VERSION 5.7 ;
  NOWIREEXTENSIONATPIN ON ;
  DIVIDERCHAR "/" ;
  BUSBITCHARS "[]" ;
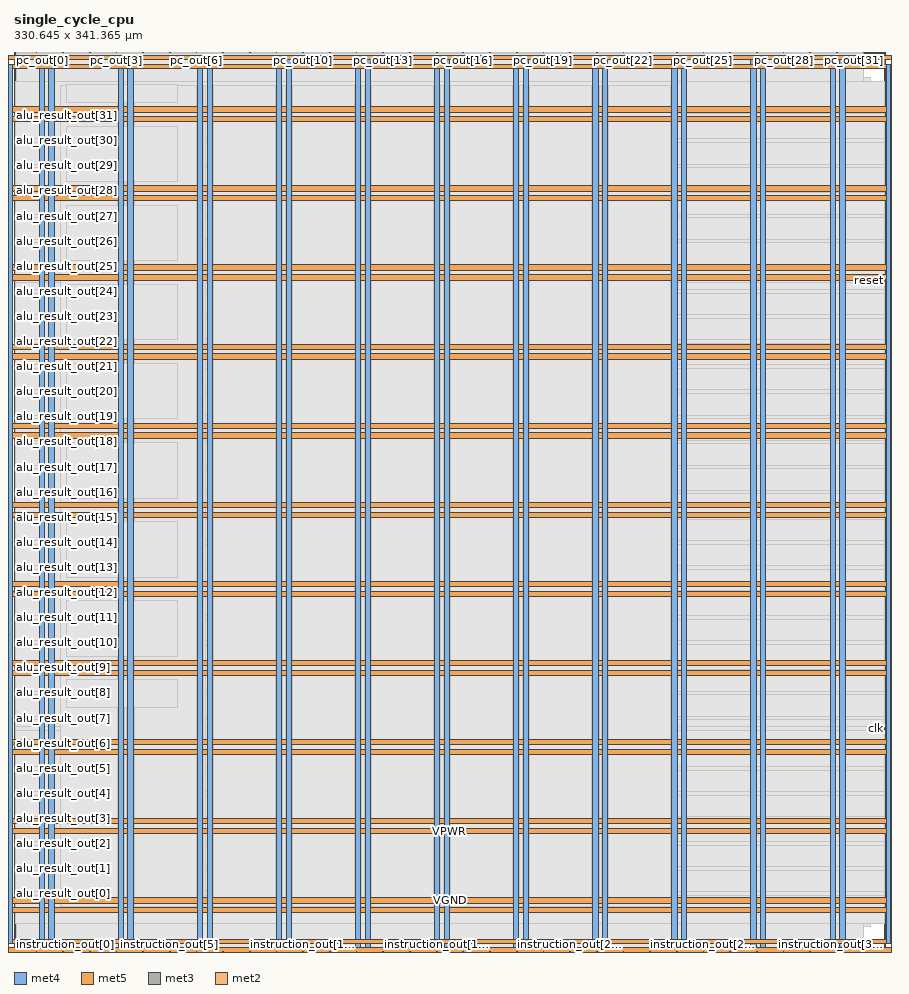
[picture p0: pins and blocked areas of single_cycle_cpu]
MACRO single_cycle_cpu
  CLASS BLOCK ;
  FOREIGN single_cycle_cpu ;
  ORIGIN 0.000 0.000 ;
  SIZE 330.645 BY 341.365 ;
  PIN VGND
    DIRECTION INOUT ;
    USE GROUND ;
    PORT
      LAYER met4 ;
        RECT -5.380 -0.020 -3.780 340.020 ;
    END
    PORT
      LAYER met4 ;
        RECT 334.060 -0.020 335.660 340.020 ;
    END
    PORT
      LAYER met5 ;
        RECT -5.380 -0.020 335.660 1.580 ;
    END
    PORT
      LAYER met5 ;
        RECT -5.380 338.420 335.660 340.020 ;
    END
    PORT
      LAYER met4 ;
        RECT 13.220 -0.020 15.220 340.020 ;
    END
    PORT
      LAYER met4 ;
        RECT 43.220 -0.020 45.220 340.020 ;
    END
    PORT
      LAYER met4 ;
        RECT 73.220 -0.020 75.220 340.020 ;
    END
    PORT
      LAYER met4 ;
        RECT 103.220 -0.020 105.220 340.020 ;
    END
    PORT
      LAYER met4 ;
        RECT 133.220 -0.020 135.220 340.020 ;
    END
    PORT
      LAYER met4 ;
        RECT 163.220 -0.020 165.220 340.020 ;
    END
    PORT
      LAYER met4 ;
        RECT 193.220 -0.020 195.220 340.020 ;
    END
    PORT
      LAYER met4 ;
        RECT 223.220 -0.020 225.220 340.020 ;
    END
    PORT
      LAYER met4 ;
        RECT 253.220 -0.020 255.220 340.020 ;
    END
    PORT
      LAYER met4 ;
        RECT 283.220 -0.020 285.220 340.020 ;
    END
    PORT
      LAYER met4 ;
        RECT 313.220 -0.020 315.220 340.020 ;
    END
    PORT
      LAYER met5 ;
        RECT -5.380 18.580 335.660 20.580 ;
    END
    PORT
      LAYER met5 ;
        RECT -5.380 48.580 335.660 50.580 ;
    END
    PORT
      LAYER met5 ;
        RECT -5.380 78.580 335.660 80.580 ;
    END
    PORT
      LAYER met5 ;
        RECT -5.380 108.580 335.660 110.580 ;
    END
    PORT
      LAYER met5 ;
        RECT -5.380 138.580 335.660 140.580 ;
    END
    PORT
      LAYER met5 ;
        RECT -5.380 168.580 335.660 170.580 ;
    END
    PORT
      LAYER met5 ;
        RECT -5.380 198.580 335.660 200.580 ;
    END
    PORT
      LAYER met5 ;
        RECT -5.380 228.580 335.660 230.580 ;
    END
    PORT
      LAYER met5 ;
        RECT -5.380 258.580 335.660 260.580 ;
    END
    PORT
      LAYER met5 ;
        RECT -5.380 288.580 335.660 290.580 ;
    END
    PORT
      LAYER met5 ;
        RECT -5.380 318.580 335.660 320.580 ;
    END
  END VGND
  PIN VPWR
    DIRECTION INOUT ;
    USE POWER ;
    PORT
      LAYER met4 ;
        RECT -2.080 3.280 -0.480 336.720 ;
    END
    PORT
      LAYER met4 ;
        RECT 330.760 3.280 332.360 336.720 ;
    END
    PORT
      LAYER met5 ;
        RECT -2.080 3.280 332.360 4.880 ;
    END
    PORT
      LAYER met5 ;
        RECT -2.080 335.120 332.360 336.720 ;
    END
    PORT
      LAYER met4 ;
        RECT 9.520 -0.020 11.520 340.020 ;
    END
    PORT
      LAYER met4 ;
        RECT 39.520 -0.020 41.520 340.020 ;
    END
    PORT
      LAYER met4 ;
        RECT 69.520 -0.020 71.520 340.020 ;
    END
    PORT
      LAYER met4 ;
        RECT 99.520 -0.020 101.520 340.020 ;
    END
    PORT
      LAYER met4 ;
        RECT 129.520 -0.020 131.520 340.020 ;
    END
    PORT
      LAYER met4 ;
        RECT 159.520 -0.020 161.520 340.020 ;
    END
    PORT
      LAYER met4 ;
        RECT 189.520 -0.020 191.520 340.020 ;
    END
    PORT
      LAYER met4 ;
        RECT 219.520 -0.020 221.520 340.020 ;
    END
    PORT
      LAYER met4 ;
        RECT 249.520 -0.020 251.520 340.020 ;
    END
    PORT
      LAYER met4 ;
        RECT 279.520 -0.020 281.520 340.020 ;
    END
    PORT
      LAYER met4 ;
        RECT 309.520 -0.020 311.520 340.020 ;
    END
    PORT
      LAYER met5 ;
        RECT -5.380 14.880 335.660 16.880 ;
    END
    PORT
      LAYER met5 ;
        RECT -5.380 44.880 335.660 46.880 ;
    END
    PORT
      LAYER met5 ;
        RECT -5.380 74.880 335.660 76.880 ;
    END
    PORT
      LAYER met5 ;
        RECT -5.380 104.880 335.660 106.880 ;
    END
    PORT
      LAYER met5 ;
        RECT -5.380 134.880 335.660 136.880 ;
    END
    PORT
      LAYER met5 ;
        RECT -5.380 164.880 335.660 166.880 ;
    END
    PORT
      LAYER met5 ;
        RECT -5.380 194.880 335.660 196.880 ;
    END
    PORT
      LAYER met5 ;
        RECT -5.380 224.880 335.660 226.880 ;
    END
    PORT
      LAYER met5 ;
        RECT -5.380 254.880 335.660 256.880 ;
    END
    PORT
      LAYER met5 ;
        RECT -5.380 284.880 335.660 286.880 ;
    END
    PORT
      LAYER met5 ;
        RECT -5.380 314.880 335.660 316.880 ;
    END
  END VPWR
  PIN alu_result_out[0]
    DIRECTION OUTPUT ;
    USE SIGNAL ;
    ANTENNADIFFAREA 0.702900 ;
    PORT
      LAYER met3 ;
        RECT 0.000 21.800 0.600 22.400 ;
    END
  END alu_result_out[0]
  PIN alu_result_out[10]
    DIRECTION OUTPUT ;
    USE SIGNAL ;
    ANTENNADIFFAREA 0.702900 ;
    PORT
      LAYER met3 ;
        RECT 0.000 117.000 0.600 117.600 ;
    END
  END alu_result_out[10]
  PIN alu_result_out[11]
    DIRECTION OUTPUT ;
    USE SIGNAL ;
    ANTENNADIFFAREA 0.702900 ;
    PORT
      LAYER met3 ;
        RECT 0.000 126.520 0.600 127.120 ;
    END
  END alu_result_out[11]
  PIN alu_result_out[12]
    DIRECTION OUTPUT ;
    USE SIGNAL ;
    ANTENNADIFFAREA 0.702900 ;
    PORT
      LAYER met3 ;
        RECT 0.000 136.040 0.600 136.640 ;
    END
  END alu_result_out[12]
  PIN alu_result_out[13]
    DIRECTION OUTPUT ;
    USE SIGNAL ;
    ANTENNADIFFAREA 0.702900 ;
    PORT
      LAYER met3 ;
        RECT 0.000 145.560 0.600 146.160 ;
    END
  END alu_result_out[13]
  PIN alu_result_out[14]
    DIRECTION OUTPUT ;
    USE SIGNAL ;
    ANTENNADIFFAREA 0.702900 ;
    PORT
      LAYER met3 ;
        RECT 0.000 155.080 0.600 155.680 ;
    END
  END alu_result_out[14]
  PIN alu_result_out[15]
    DIRECTION OUTPUT ;
    USE SIGNAL ;
    ANTENNADIFFAREA 0.702900 ;
    PORT
      LAYER met3 ;
        RECT 0.000 164.600 0.600 165.200 ;
    END
  END alu_result_out[15]
  PIN alu_result_out[16]
    DIRECTION OUTPUT ;
    USE SIGNAL ;
    ANTENNADIFFAREA 0.702900 ;
    PORT
      LAYER met3 ;
        RECT 0.000 174.120 0.600 174.720 ;
    END
  END alu_result_out[16]
  PIN alu_result_out[17]
    DIRECTION OUTPUT ;
    USE SIGNAL ;
    ANTENNADIFFAREA 0.702900 ;
    PORT
      LAYER met3 ;
        RECT 0.000 183.640 0.600 184.240 ;
    END
  END alu_result_out[17]
  PIN alu_result_out[18]
    DIRECTION OUTPUT ;
    USE SIGNAL ;
    ANTENNADIFFAREA 0.702900 ;
    PORT
      LAYER met3 ;
        RECT 0.000 193.160 0.600 193.760 ;
    END
  END alu_result_out[18]
  PIN alu_result_out[19]
    DIRECTION OUTPUT ;
    USE SIGNAL ;
    ANTENNADIFFAREA 0.702900 ;
    PORT
      LAYER met3 ;
        RECT 0.000 202.680 0.600 203.280 ;
    END
  END alu_result_out[19]
  PIN alu_result_out[1]
    DIRECTION OUTPUT ;
    USE SIGNAL ;
    ANTENNADIFFAREA 0.702900 ;
    PORT
      LAYER met3 ;
        RECT 0.000 31.320 0.600 31.920 ;
    END
  END alu_result_out[1]
  PIN alu_result_out[20]
    DIRECTION OUTPUT ;
    USE SIGNAL ;
    ANTENNADIFFAREA 0.702900 ;
    PORT
      LAYER met3 ;
        RECT 0.000 212.200 0.600 212.800 ;
    END
  END alu_result_out[20]
  PIN alu_result_out[21]
    DIRECTION OUTPUT ;
    USE SIGNAL ;
    ANTENNADIFFAREA 0.702900 ;
    PORT
      LAYER met3 ;
        RECT 0.000 221.720 0.600 222.320 ;
    END
  END alu_result_out[21]
  PIN alu_result_out[22]
    DIRECTION OUTPUT ;
    USE SIGNAL ;
    ANTENNADIFFAREA 0.702900 ;
    PORT
      LAYER met3 ;
        RECT 0.000 231.240 0.600 231.840 ;
    END
  END alu_result_out[22]
  PIN alu_result_out[23]
    DIRECTION OUTPUT ;
    USE SIGNAL ;
    ANTENNADIFFAREA 0.702900 ;
    PORT
      LAYER met3 ;
        RECT 0.000 240.760 0.600 241.360 ;
    END
  END alu_result_out[23]
  PIN alu_result_out[24]
    DIRECTION OUTPUT ;
    USE SIGNAL ;
    ANTENNADIFFAREA 0.702900 ;
    PORT
      LAYER met3 ;
        RECT 0.000 250.280 0.600 250.880 ;
    END
  END alu_result_out[24]
  PIN alu_result_out[25]
    DIRECTION OUTPUT ;
    USE SIGNAL ;
    ANTENNADIFFAREA 0.702900 ;
    PORT
      LAYER met3 ;
        RECT 0.000 259.800 0.600 260.400 ;
    END
  END alu_result_out[25]
  PIN alu_result_out[26]
    DIRECTION OUTPUT ;
    USE SIGNAL ;
    ANTENNADIFFAREA 0.702900 ;
    PORT
      LAYER met3 ;
        RECT 0.000 269.320 0.600 269.920 ;
    END
  END alu_result_out[26]
  PIN alu_result_out[27]
    DIRECTION OUTPUT ;
    USE SIGNAL ;
    ANTENNADIFFAREA 0.702900 ;
    PORT
      LAYER met3 ;
        RECT 0.000 278.840 0.600 279.440 ;
    END
  END alu_result_out[27]
  PIN alu_result_out[28]
    DIRECTION OUTPUT ;
    USE SIGNAL ;
    ANTENNADIFFAREA 0.702900 ;
    PORT
      LAYER met3 ;
        RECT 0.000 288.360 0.600 288.960 ;
    END
  END alu_result_out[28]
  PIN alu_result_out[29]
    DIRECTION OUTPUT ;
    USE SIGNAL ;
    ANTENNADIFFAREA 0.702900 ;
    PORT
      LAYER met3 ;
        RECT 0.000 297.880 0.600 298.480 ;
    END
  END alu_result_out[29]
  PIN alu_result_out[2]
    DIRECTION OUTPUT ;
    USE SIGNAL ;
    ANTENNADIFFAREA 0.702900 ;
    PORT
      LAYER met3 ;
        RECT 0.000 40.840 0.600 41.440 ;
    END
  END alu_result_out[2]
  PIN alu_result_out[30]
    DIRECTION OUTPUT ;
    USE SIGNAL ;
    ANTENNADIFFAREA 0.702900 ;
    PORT
      LAYER met3 ;
        RECT 0.000 307.400 0.600 308.000 ;
    END
  END alu_result_out[30]
  PIN alu_result_out[31]
    DIRECTION OUTPUT ;
    USE SIGNAL ;
    ANTENNADIFFAREA 0.702900 ;
    PORT
      LAYER met3 ;
        RECT 0.000 316.920 0.600 317.520 ;
    END
  END alu_result_out[31]
  PIN alu_result_out[3]
    DIRECTION OUTPUT ;
    USE SIGNAL ;
    ANTENNADIFFAREA 0.702900 ;
    PORT
      LAYER met3 ;
        RECT 0.000 50.360 0.600 50.960 ;
    END
  END alu_result_out[3]
  PIN alu_result_out[4]
    DIRECTION OUTPUT ;
    USE SIGNAL ;
    ANTENNADIFFAREA 0.702900 ;
    PORT
      LAYER met3 ;
        RECT 0.000 59.880 0.600 60.480 ;
    END
  END alu_result_out[4]
  PIN alu_result_out[5]
    DIRECTION OUTPUT ;
    USE SIGNAL ;
    ANTENNADIFFAREA 0.702900 ;
    PORT
      LAYER met3 ;
        RECT 0.000 69.400 0.600 70.000 ;
    END
  END alu_result_out[5]
  PIN alu_result_out[6]
    DIRECTION OUTPUT ;
    USE SIGNAL ;
    ANTENNADIFFAREA 0.702900 ;
    PORT
      LAYER met3 ;
        RECT 0.000 78.920 0.600 79.520 ;
    END
  END alu_result_out[6]
  PIN alu_result_out[7]
    DIRECTION OUTPUT ;
    USE SIGNAL ;
    ANTENNADIFFAREA 0.702900 ;
    PORT
      LAYER met3 ;
        RECT 0.000 88.440 0.600 89.040 ;
    END
  END alu_result_out[7]
  PIN alu_result_out[8]
    DIRECTION OUTPUT ;
    USE SIGNAL ;
    ANTENNADIFFAREA 0.702900 ;
    PORT
      LAYER met3 ;
        RECT 0.000 97.960 0.600 98.560 ;
    END
  END alu_result_out[8]
  PIN alu_result_out[9]
    DIRECTION OUTPUT ;
    USE SIGNAL ;
    ANTENNADIFFAREA 0.702900 ;
    PORT
      LAYER met3 ;
        RECT 0.000 107.480 0.600 108.080 ;
    END
  END alu_result_out[9]
  PIN clk
    DIRECTION INPUT ;
    USE SIGNAL ;
    ANTENNAGATEAREA 0.852000 ;
    PORT
      LAYER met3 ;
        RECT 330.045 84.360 330.645 84.960 ;
    END
  END clk
  PIN instruction_out[0]
    DIRECTION OUTPUT ;
    USE SIGNAL ;
    PORT
      LAYER met2 ;
        RECT 8.370 0.000 8.650 0.280 ;
    END
  END instruction_out[0]
  PIN instruction_out[10]
    DIRECTION OUTPUT ;
    USE SIGNAL ;
    ANTENNADIFFAREA 0.702900 ;
    PORT
      LAYER met2 ;
        RECT 109.570 0.000 109.850 0.280 ;
    END
  END instruction_out[10]
  PIN instruction_out[11]
    DIRECTION OUTPUT ;
    USE SIGNAL ;
    ANTENNADIFFAREA 0.702900 ;
    PORT
      LAYER met2 ;
        RECT 119.690 0.000 119.970 0.280 ;
    END
  END instruction_out[11]
  PIN instruction_out[12]
    DIRECTION OUTPUT ;
    USE SIGNAL ;
    ANTENNADIFFAREA 0.702900 ;
    PORT
      LAYER met2 ;
        RECT 129.810 0.000 130.090 0.280 ;
    END
  END instruction_out[12]
  PIN instruction_out[13]
    DIRECTION OUTPUT ;
    USE SIGNAL ;
    ANTENNADIFFAREA 0.702900 ;
    PORT
      LAYER met2 ;
        RECT 139.930 0.000 140.210 0.280 ;
    END
  END instruction_out[13]
  PIN instruction_out[14]
    DIRECTION OUTPUT ;
    USE SIGNAL ;
    ANTENNADIFFAREA 0.702900 ;
    PORT
      LAYER met2 ;
        RECT 150.050 0.000 150.330 0.280 ;
    END
  END instruction_out[14]
  PIN instruction_out[15]
    DIRECTION OUTPUT ;
    USE SIGNAL ;
    ANTENNADIFFAREA 0.702900 ;
    PORT
      LAYER met2 ;
        RECT 160.170 0.000 160.450 0.280 ;
    END
  END instruction_out[15]
  PIN instruction_out[16]
    DIRECTION OUTPUT ;
    USE SIGNAL ;
    ANTENNADIFFAREA 0.702900 ;
    PORT
      LAYER met2 ;
        RECT 170.290 0.000 170.570 0.280 ;
    END
  END instruction_out[16]
  PIN instruction_out[17]
    DIRECTION OUTPUT ;
    USE SIGNAL ;
    ANTENNADIFFAREA 0.702900 ;
    PORT
      LAYER met2 ;
        RECT 180.410 0.000 180.690 0.280 ;
    END
  END instruction_out[17]
  PIN instruction_out[18]
    DIRECTION OUTPUT ;
    USE SIGNAL ;
    ANTENNADIFFAREA 0.702900 ;
    PORT
      LAYER met2 ;
        RECT 190.530 0.000 190.810 0.280 ;
    END
  END instruction_out[18]
  PIN instruction_out[19]
    DIRECTION OUTPUT ;
    USE SIGNAL ;
    PORT
      LAYER met2 ;
        RECT 200.650 0.000 200.930 0.280 ;
    END
  END instruction_out[19]
  PIN instruction_out[1]
    DIRECTION OUTPUT ;
    USE SIGNAL ;
    PORT
      LAYER met2 ;
        RECT 18.490 0.000 18.770 0.280 ;
    END
  END instruction_out[1]
  PIN instruction_out[20]
    DIRECTION OUTPUT ;
    USE SIGNAL ;
    ANTENNADIFFAREA 0.702900 ;
    PORT
      LAYER met2 ;
        RECT 210.770 0.000 211.050 0.280 ;
    END
  END instruction_out[20]
  PIN instruction_out[21]
    DIRECTION OUTPUT ;
    USE SIGNAL ;
    ANTENNADIFFAREA 0.702900 ;
    PORT
      LAYER met2 ;
        RECT 220.890 0.000 221.170 0.280 ;
    END
  END instruction_out[21]
  PIN instruction_out[22]
    DIRECTION OUTPUT ;
    USE SIGNAL ;
    ANTENNADIFFAREA 0.702900 ;
    PORT
      LAYER met2 ;
        RECT 231.010 0.000 231.290 0.280 ;
    END
  END instruction_out[22]
  PIN instruction_out[23]
    DIRECTION OUTPUT ;
    USE SIGNAL ;
    ANTENNADIFFAREA 0.702900 ;
    PORT
      LAYER met2 ;
        RECT 241.130 0.000 241.410 0.280 ;
    END
  END instruction_out[23]
  PIN instruction_out[24]
    DIRECTION OUTPUT ;
    USE SIGNAL ;
    ANTENNADIFFAREA 0.702900 ;
    PORT
      LAYER met2 ;
        RECT 251.250 0.000 251.530 0.280 ;
    END
  END instruction_out[24]
  PIN instruction_out[25]
    DIRECTION OUTPUT ;
    USE SIGNAL ;
    ANTENNADIFFAREA 0.702900 ;
    PORT
      LAYER met2 ;
        RECT 261.370 0.000 261.650 0.280 ;
    END
  END instruction_out[25]
  PIN instruction_out[26]
    DIRECTION OUTPUT ;
    USE SIGNAL ;
    ANTENNADIFFAREA 0.702900 ;
    PORT
      LAYER met2 ;
        RECT 271.490 0.000 271.770 0.280 ;
    END
  END instruction_out[26]
  PIN instruction_out[27]
    DIRECTION OUTPUT ;
    USE SIGNAL ;
    ANTENNADIFFAREA 0.702900 ;
    PORT
      LAYER met2 ;
        RECT 281.610 0.000 281.890 0.280 ;
    END
  END instruction_out[27]
  PIN instruction_out[28]
    DIRECTION OUTPUT ;
    USE SIGNAL ;
    ANTENNADIFFAREA 0.702900 ;
    PORT
      LAYER met2 ;
        RECT 291.730 0.000 292.010 0.280 ;
    END
  END instruction_out[28]
  PIN instruction_out[29]
    DIRECTION OUTPUT ;
    USE SIGNAL ;
    PORT
      LAYER met2 ;
        RECT 301.850 0.000 302.130 0.280 ;
    END
  END instruction_out[29]
  PIN instruction_out[2]
    DIRECTION OUTPUT ;
    USE SIGNAL ;
    ANTENNADIFFAREA 0.702900 ;
    PORT
      LAYER met2 ;
        RECT 28.610 0.000 28.890 0.280 ;
    END
  END instruction_out[2]
  PIN instruction_out[30]
    DIRECTION OUTPUT ;
    USE SIGNAL ;
    ANTENNADIFFAREA 0.702900 ;
    PORT
      LAYER met2 ;
        RECT 311.970 0.000 312.250 0.280 ;
    END
  END instruction_out[30]
  PIN instruction_out[31]
    DIRECTION OUTPUT ;
    USE SIGNAL ;
    PORT
      LAYER met2 ;
        RECT 322.090 0.000 322.370 0.280 ;
    END
  END instruction_out[31]
  PIN instruction_out[3]
    DIRECTION OUTPUT ;
    USE SIGNAL ;
    ANTENNADIFFAREA 0.702900 ;
    PORT
      LAYER met2 ;
        RECT 38.730 0.000 39.010 0.280 ;
    END
  END instruction_out[3]
  PIN instruction_out[4]
    DIRECTION OUTPUT ;
    USE SIGNAL ;
    ANTENNADIFFAREA 0.702900 ;
    PORT
      LAYER met2 ;
        RECT 48.850 0.000 49.130 0.280 ;
    END
  END instruction_out[4]
  PIN instruction_out[5]
    DIRECTION OUTPUT ;
    USE SIGNAL ;
    ANTENNADIFFAREA 0.702900 ;
    PORT
      LAYER met2 ;
        RECT 58.970 0.000 59.250 0.280 ;
    END
  END instruction_out[5]
  PIN instruction_out[6]
    DIRECTION OUTPUT ;
    USE SIGNAL ;
    ANTENNADIFFAREA 0.702900 ;
    PORT
      LAYER met2 ;
        RECT 69.090 0.000 69.370 0.280 ;
    END
  END instruction_out[6]
  PIN instruction_out[7]
    DIRECTION OUTPUT ;
    USE SIGNAL ;
    ANTENNADIFFAREA 0.702900 ;
    PORT
      LAYER met2 ;
        RECT 79.210 0.000 79.490 0.280 ;
    END
  END instruction_out[7]
  PIN instruction_out[8]
    DIRECTION OUTPUT ;
    USE SIGNAL ;
    ANTENNADIFFAREA 0.702900 ;
    PORT
      LAYER met2 ;
        RECT 89.330 0.000 89.610 0.280 ;
    END
  END instruction_out[8]
  PIN instruction_out[9]
    DIRECTION OUTPUT ;
    USE SIGNAL ;
    ANTENNADIFFAREA 0.702900 ;
    PORT
      LAYER met2 ;
        RECT 99.450 0.000 99.730 0.280 ;
    END
  END instruction_out[9]
  PIN pc_out[0]
    DIRECTION OUTPUT ;
    USE SIGNAL ;
    ANTENNADIFFAREA 0.702900 ;
    PORT
      LAYER met2 ;
        RECT 8.370 341.085 8.650 341.365 ;
    END
  END pc_out[0]
  PIN pc_out[10]
    DIRECTION OUTPUT ;
    USE SIGNAL ;
    ANTENNADIFFAREA 0.702900 ;
    PORT
      LAYER met2 ;
        RECT 109.570 341.085 109.850 341.365 ;
    END
  END pc_out[10]
  PIN pc_out[11]
    DIRECTION OUTPUT ;
    USE SIGNAL ;
    ANTENNADIFFAREA 0.702900 ;
    PORT
      LAYER met2 ;
        RECT 119.690 341.085 119.970 341.365 ;
    END
  END pc_out[11]
  PIN pc_out[12]
    DIRECTION OUTPUT ;
    USE SIGNAL ;
    ANTENNADIFFAREA 0.702900 ;
    PORT
      LAYER met2 ;
        RECT 129.810 341.085 130.090 341.365 ;
    END
  END pc_out[12]
  PIN pc_out[13]
    DIRECTION OUTPUT ;
    USE SIGNAL ;
    ANTENNADIFFAREA 0.702900 ;
    PORT
      LAYER met2 ;
        RECT 139.930 341.085 140.210 341.365 ;
    END
  END pc_out[13]
  PIN pc_out[14]
    DIRECTION OUTPUT ;
    USE SIGNAL ;
    ANTENNADIFFAREA 0.702900 ;
    PORT
      LAYER met2 ;
        RECT 150.050 341.085 150.330 341.365 ;
    END
  END pc_out[14]
  PIN pc_out[15]
    DIRECTION OUTPUT ;
    USE SIGNAL ;
    ANTENNADIFFAREA 0.702900 ;
    PORT
      LAYER met2 ;
        RECT 160.170 341.085 160.450 341.365 ;
    END
  END pc_out[15]
  PIN pc_out[16]
    DIRECTION OUTPUT ;
    USE SIGNAL ;
    ANTENNADIFFAREA 0.702900 ;
    PORT
      LAYER met2 ;
        RECT 170.290 341.085 170.570 341.365 ;
    END
  END pc_out[16]
  PIN pc_out[17]
    DIRECTION OUTPUT ;
    USE SIGNAL ;
    ANTENNADIFFAREA 0.702900 ;
    PORT
      LAYER met2 ;
        RECT 180.410 341.085 180.690 341.365 ;
    END
  END pc_out[17]
  PIN pc_out[18]
    DIRECTION OUTPUT ;
    USE SIGNAL ;
    ANTENNADIFFAREA 0.702900 ;
    PORT
      LAYER met2 ;
        RECT 190.530 341.085 190.810 341.365 ;
    END
  END pc_out[18]
  PIN pc_out[19]
    DIRECTION OUTPUT ;
    USE SIGNAL ;
    ANTENNADIFFAREA 0.702900 ;
    PORT
      LAYER met2 ;
        RECT 200.650 341.085 200.930 341.365 ;
    END
  END pc_out[19]
  PIN pc_out[1]
    DIRECTION OUTPUT ;
    USE SIGNAL ;
    ANTENNADIFFAREA 0.702900 ;
    PORT
      LAYER met2 ;
        RECT 18.490 341.085 18.770 341.365 ;
    END
  END pc_out[1]
  PIN pc_out[20]
    DIRECTION OUTPUT ;
    USE SIGNAL ;
    ANTENNADIFFAREA 0.702900 ;
    PORT
      LAYER met2 ;
        RECT 210.770 341.085 211.050 341.365 ;
    END
  END pc_out[20]
  PIN pc_out[21]
    DIRECTION OUTPUT ;
    USE SIGNAL ;
    ANTENNADIFFAREA 0.702900 ;
    PORT
      LAYER met2 ;
        RECT 220.890 341.085 221.170 341.365 ;
    END
  END pc_out[21]
  PIN pc_out[22]
    DIRECTION OUTPUT ;
    USE SIGNAL ;
    ANTENNADIFFAREA 0.702900 ;
    PORT
      LAYER met2 ;
        RECT 231.010 341.085 231.290 341.365 ;
    END
  END pc_out[22]
  PIN pc_out[23]
    DIRECTION OUTPUT ;
    USE SIGNAL ;
    ANTENNADIFFAREA 0.702900 ;
    PORT
      LAYER met2 ;
        RECT 241.130 341.085 241.410 341.365 ;
    END
  END pc_out[23]
  PIN pc_out[24]
    DIRECTION OUTPUT ;
    USE SIGNAL ;
    ANTENNADIFFAREA 0.702900 ;
    PORT
      LAYER met2 ;
        RECT 251.250 341.085 251.530 341.365 ;
    END
  END pc_out[24]
  PIN pc_out[25]
    DIRECTION OUTPUT ;
    USE SIGNAL ;
    ANTENNADIFFAREA 0.702900 ;
    PORT
      LAYER met2 ;
        RECT 261.370 341.085 261.650 341.365 ;
    END
  END pc_out[25]
  PIN pc_out[26]
    DIRECTION OUTPUT ;
    USE SIGNAL ;
    ANTENNADIFFAREA 0.702900 ;
    PORT
      LAYER met2 ;
        RECT 271.490 341.085 271.770 341.365 ;
    END
  END pc_out[26]
  PIN pc_out[27]
    DIRECTION OUTPUT ;
    USE SIGNAL ;
    ANTENNADIFFAREA 0.702900 ;
    PORT
      LAYER met2 ;
        RECT 281.610 341.085 281.890 341.365 ;
    END
  END pc_out[27]
  PIN pc_out[28]
    DIRECTION OUTPUT ;
    USE SIGNAL ;
    ANTENNADIFFAREA 0.702900 ;
    PORT
      LAYER met2 ;
        RECT 291.730 341.085 292.010 341.365 ;
    END
  END pc_out[28]
  PIN pc_out[29]
    DIRECTION OUTPUT ;
    USE SIGNAL ;
    ANTENNADIFFAREA 0.702900 ;
    PORT
      LAYER met2 ;
        RECT 301.850 341.085 302.130 341.365 ;
    END
  END pc_out[29]
  PIN pc_out[2]
    DIRECTION OUTPUT ;
    USE SIGNAL ;
    ANTENNADIFFAREA 0.702900 ;
    PORT
      LAYER met2 ;
        RECT 28.610 341.085 28.890 341.365 ;
    END
  END pc_out[2]
  PIN pc_out[30]
    DIRECTION OUTPUT ;
    USE SIGNAL ;
    ANTENNADIFFAREA 0.702900 ;
    PORT
      LAYER met2 ;
        RECT 311.970 341.085 312.250 341.365 ;
    END
  END pc_out[30]
  PIN pc_out[31]
    DIRECTION OUTPUT ;
    USE SIGNAL ;
    ANTENNADIFFAREA 0.702900 ;
    PORT
      LAYER met2 ;
        RECT 322.090 341.085 322.370 341.365 ;
    END
  END pc_out[31]
  PIN pc_out[3]
    DIRECTION OUTPUT ;
    USE SIGNAL ;
    ANTENNADIFFAREA 0.702900 ;
    PORT
      LAYER met2 ;
        RECT 38.730 341.085 39.010 341.365 ;
    END
  END pc_out[3]
  PIN pc_out[4]
    DIRECTION OUTPUT ;
    USE SIGNAL ;
    ANTENNADIFFAREA 0.702900 ;
    PORT
      LAYER met2 ;
        RECT 48.850 341.085 49.130 341.365 ;
    END
  END pc_out[4]
  PIN pc_out[5]
    DIRECTION OUTPUT ;
    USE SIGNAL ;
    ANTENNADIFFAREA 0.702900 ;
    PORT
      LAYER met2 ;
        RECT 58.970 341.085 59.250 341.365 ;
    END
  END pc_out[5]
  PIN pc_out[6]
    DIRECTION OUTPUT ;
    USE SIGNAL ;
    ANTENNADIFFAREA 0.702900 ;
    PORT
      LAYER met2 ;
        RECT 69.090 341.085 69.370 341.365 ;
    END
  END pc_out[6]
  PIN pc_out[7]
    DIRECTION OUTPUT ;
    USE SIGNAL ;
    ANTENNADIFFAREA 0.702900 ;
    PORT
      LAYER met2 ;
        RECT 79.210 341.085 79.490 341.365 ;
    END
  END pc_out[7]
  PIN pc_out[8]
    DIRECTION OUTPUT ;
    USE SIGNAL ;
    ANTENNADIFFAREA 0.702900 ;
    PORT
      LAYER met2 ;
        RECT 89.330 341.085 89.610 341.365 ;
    END
  END pc_out[8]
  PIN pc_out[9]
    DIRECTION OUTPUT ;
    USE SIGNAL ;
    ANTENNADIFFAREA 0.702900 ;
    PORT
      LAYER met2 ;
        RECT 99.450 341.085 99.730 341.365 ;
    END
  END pc_out[9]
  PIN reset
    DIRECTION INPUT ;
    USE SIGNAL ;
    ANTENNAGATEAREA 0.393000 ;
    PORT
      LAYER met3 ;
        RECT 330.045 254.360 330.645 254.960 ;
    END
  END reset
  OBS
      LAYER nwell ;
        RECT 5.330 10.795 324.950 329.310 ;
      LAYER li1 ;
        RECT 5.520 10.795 324.760 329.205 ;
      LAYER met1 ;
        RECT 0.990 9.560 324.760 331.800 ;
      LAYER met2 ;
        RECT 1.010 340.805 8.090 341.295 ;
        RECT 8.930 340.805 18.210 341.295 ;
        RECT 19.050 340.805 28.330 341.295 ;
        RECT 29.170 340.805 38.450 341.295 ;
        RECT 39.290 340.805 48.570 341.295 ;
        RECT 49.410 340.805 58.690 341.295 ;
        RECT 59.530 340.805 68.810 341.295 ;
        RECT 69.650 340.805 78.930 341.295 ;
        RECT 79.770 340.805 89.050 341.295 ;
        RECT 89.890 340.805 99.170 341.295 ;
        RECT 100.010 340.805 109.290 341.295 ;
        RECT 110.130 340.805 119.410 341.295 ;
        RECT 120.250 340.805 129.530 341.295 ;
        RECT 130.370 340.805 139.650 341.295 ;
        RECT 140.490 340.805 149.770 341.295 ;
        RECT 150.610 340.805 159.890 341.295 ;
        RECT 160.730 340.805 170.010 341.295 ;
        RECT 170.850 340.805 180.130 341.295 ;
        RECT 180.970 340.805 190.250 341.295 ;
        RECT 191.090 340.805 200.370 341.295 ;
        RECT 201.210 340.805 210.490 341.295 ;
        RECT 211.330 340.805 220.610 341.295 ;
        RECT 221.450 340.805 230.730 341.295 ;
        RECT 231.570 340.805 240.850 341.295 ;
        RECT 241.690 340.805 250.970 341.295 ;
        RECT 251.810 340.805 261.090 341.295 ;
        RECT 261.930 340.805 271.210 341.295 ;
        RECT 272.050 340.805 281.330 341.295 ;
        RECT 282.170 340.805 291.450 341.295 ;
        RECT 292.290 340.805 301.570 341.295 ;
        RECT 302.410 340.805 311.690 341.295 ;
        RECT 312.530 340.805 321.810 341.295 ;
        RECT 1.010 0.560 322.360 340.805 ;
        RECT 1.010 0.070 8.090 0.560 ;
        RECT 8.930 0.070 18.210 0.560 ;
        RECT 19.050 0.070 28.330 0.560 ;
        RECT 29.170 0.070 38.450 0.560 ;
        RECT 39.290 0.070 48.570 0.560 ;
        RECT 49.410 0.070 58.690 0.560 ;
        RECT 59.530 0.070 68.810 0.560 ;
        RECT 69.650 0.070 78.930 0.560 ;
        RECT 79.770 0.070 89.050 0.560 ;
        RECT 89.890 0.070 99.170 0.560 ;
        RECT 100.010 0.070 109.290 0.560 ;
        RECT 110.130 0.070 119.410 0.560 ;
        RECT 120.250 0.070 129.530 0.560 ;
        RECT 130.370 0.070 139.650 0.560 ;
        RECT 140.490 0.070 149.770 0.560 ;
        RECT 150.610 0.070 159.890 0.560 ;
        RECT 160.730 0.070 170.010 0.560 ;
        RECT 170.850 0.070 180.130 0.560 ;
        RECT 180.970 0.070 190.250 0.560 ;
        RECT 191.090 0.070 200.370 0.560 ;
        RECT 201.210 0.070 210.490 0.560 ;
        RECT 211.330 0.070 220.610 0.560 ;
        RECT 221.450 0.070 230.730 0.560 ;
        RECT 231.570 0.070 240.850 0.560 ;
        RECT 241.690 0.070 250.970 0.560 ;
        RECT 251.810 0.070 261.090 0.560 ;
        RECT 261.930 0.070 271.210 0.560 ;
        RECT 272.050 0.070 281.330 0.560 ;
        RECT 282.170 0.070 291.450 0.560 ;
        RECT 292.290 0.070 301.570 0.560 ;
        RECT 302.410 0.070 311.690 0.560 ;
        RECT 312.530 0.070 321.810 0.560 ;
      LAYER met3 ;
        RECT 0.600 317.920 330.045 330.305 ;
        RECT 1.000 316.520 330.045 317.920 ;
        RECT 0.600 308.400 330.045 316.520 ;
        RECT 1.000 307.000 330.045 308.400 ;
        RECT 0.600 298.880 330.045 307.000 ;
        RECT 1.000 297.480 330.045 298.880 ;
        RECT 0.600 289.360 330.045 297.480 ;
        RECT 1.000 287.960 330.045 289.360 ;
        RECT 0.600 279.840 330.045 287.960 ;
        RECT 1.000 278.440 330.045 279.840 ;
        RECT 0.600 270.320 330.045 278.440 ;
        RECT 1.000 268.920 330.045 270.320 ;
        RECT 0.600 260.800 330.045 268.920 ;
        RECT 1.000 259.400 330.045 260.800 ;
        RECT 0.600 255.360 330.045 259.400 ;
        RECT 0.600 253.960 329.645 255.360 ;
        RECT 0.600 251.280 330.045 253.960 ;
        RECT 1.000 249.880 330.045 251.280 ;
        RECT 0.600 241.760 330.045 249.880 ;
        RECT 1.000 240.360 330.045 241.760 ;
        RECT 0.600 232.240 330.045 240.360 ;
        RECT 1.000 230.840 330.045 232.240 ;
        RECT 0.600 222.720 330.045 230.840 ;
        RECT 1.000 221.320 330.045 222.720 ;
        RECT 0.600 213.200 330.045 221.320 ;
        RECT 1.000 211.800 330.045 213.200 ;
        RECT 0.600 203.680 330.045 211.800 ;
        RECT 1.000 202.280 330.045 203.680 ;
        RECT 0.600 194.160 330.045 202.280 ;
        RECT 1.000 192.760 330.045 194.160 ;
        RECT 0.600 184.640 330.045 192.760 ;
        RECT 1.000 183.240 330.045 184.640 ;
        RECT 0.600 175.120 330.045 183.240 ;
        RECT 1.000 173.720 330.045 175.120 ;
        RECT 0.600 165.600 330.045 173.720 ;
        RECT 1.000 164.200 330.045 165.600 ;
        RECT 0.600 156.080 330.045 164.200 ;
        RECT 1.000 154.680 330.045 156.080 ;
        RECT 0.600 146.560 330.045 154.680 ;
        RECT 1.000 145.160 330.045 146.560 ;
        RECT 0.600 137.040 330.045 145.160 ;
        RECT 1.000 135.640 330.045 137.040 ;
        RECT 0.600 127.520 330.045 135.640 ;
        RECT 1.000 126.120 330.045 127.520 ;
        RECT 0.600 118.000 330.045 126.120 ;
        RECT 1.000 116.600 330.045 118.000 ;
        RECT 0.600 108.480 330.045 116.600 ;
        RECT 1.000 107.080 330.045 108.480 ;
        RECT 0.600 98.960 330.045 107.080 ;
        RECT 1.000 97.560 330.045 98.960 ;
        RECT 0.600 89.440 330.045 97.560 ;
        RECT 1.000 88.040 330.045 89.440 ;
        RECT 0.600 85.360 330.045 88.040 ;
        RECT 0.600 83.960 329.645 85.360 ;
        RECT 0.600 79.920 330.045 83.960 ;
        RECT 1.000 78.520 330.045 79.920 ;
        RECT 0.600 70.400 330.045 78.520 ;
        RECT 1.000 69.000 330.045 70.400 ;
        RECT 0.600 60.880 330.045 69.000 ;
        RECT 1.000 59.480 330.045 60.880 ;
        RECT 0.600 51.360 330.045 59.480 ;
        RECT 1.000 49.960 330.045 51.360 ;
        RECT 0.600 41.840 330.045 49.960 ;
        RECT 1.000 40.440 330.045 41.840 ;
        RECT 0.600 32.320 330.045 40.440 ;
        RECT 1.000 30.920 330.045 32.320 ;
        RECT 0.600 22.800 330.045 30.920 ;
        RECT 1.000 21.400 330.045 22.800 ;
        RECT 0.600 10.715 330.045 21.400 ;
      LAYER met4 ;
        RECT 17.775 17.175 39.120 328.690 ;
        RECT 41.920 17.175 42.820 328.690 ;
        RECT 45.620 17.175 69.120 328.690 ;
        RECT 71.920 17.175 72.820 328.690 ;
        RECT 75.620 17.175 99.120 328.690 ;
        RECT 101.920 17.175 102.820 328.690 ;
        RECT 105.620 17.175 129.120 328.690 ;
        RECT 131.920 17.175 132.820 328.690 ;
        RECT 135.620 17.175 159.120 328.690 ;
        RECT 161.920 17.175 162.820 328.690 ;
        RECT 165.620 17.175 189.120 328.690 ;
        RECT 191.920 17.175 192.820 328.690 ;
        RECT 195.620 17.175 219.120 328.690 ;
        RECT 221.920 17.175 222.820 328.690 ;
        RECT 225.620 17.175 249.025 328.690 ;
      LAYER met5 ;
        RECT 19.900 322.180 61.980 328.900 ;
        RECT 19.900 292.180 61.980 313.280 ;
        RECT 19.900 262.180 61.980 283.280 ;
        RECT 19.900 232.180 61.980 253.280 ;
        RECT 19.900 202.180 61.980 223.280 ;
        RECT 19.900 172.180 61.980 193.280 ;
        RECT 19.900 142.180 61.980 163.280 ;
        RECT 19.900 112.180 61.980 133.280 ;
        RECT 19.900 92.700 61.980 103.280 ;
  END
END single_cycle_cpu
END LIBRARY

